VERSION 5.8 ;
BUSBITCHARS "[]" ;
DIVIDERCHAR "/" ;
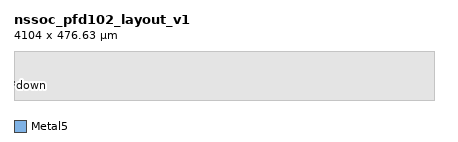
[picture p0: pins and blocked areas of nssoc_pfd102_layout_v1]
MACRO nssoc_pfd102_layout_v1
  CLASS BLOCK ;
  ORIGIN 0 0 ;
  SIZE 4104.000 BY 476.630 ;
  PIN ref
    DIRECTION INPUT ;
    USE SIGNAL ;
    PORT
      LAYER Metal5 ;
      RECT 0.000 151.430 2.000 152.630 ;
    END
  END ref
  PIN fb
    DIRECTION INPUT ;
    USE SIGNAL ;
    PORT
      LAYER Metal5 ;
      RECT 0.000 145.430 2.000 146.630 ;
    END
  END fb
  PIN reset
    DIRECTION INPUT ;
    USE SIGNAL ;
    PORT
      LAYER Metal5 ;
      RECT 0.000 157.430 2.000 158.630 ;
    END
  END reset
  PIN up
    DIRECTION OUTPUT ;
    USE SIGNAL ;
    PORT
      LAYER Metal5 ;
      RECT 0.000 169.430 2.000 170.630 ;
    END
  END up
  PIN down
    DIRECTION OUTPUT ;
    USE SIGNAL ;
    PORT
      LAYER Metal5 ;
      RECT 0.000 139.430 2.000 140.630 ;
    END
  END down
  PIN vdd
    DIRECTION INOUT ;
    USE POWER ;
    PORT
      LAYER Metal5 ;
      RECT 0.000 175.430 2.000 176.630 ;
    END
  END vdd
  PIN vss
    DIRECTION INOUT ;
    USE GROUND ;
    PORT
      LAYER Metal5 ;
      RECT 0.000 181.430 2.000 182.630 ;
    END
  END vss
  PIN sub
    DIRECTION INOUT ;
    USE GROUND ;
    PORT
      LAYER Metal5 ;
      RECT 0.000 163.430 2.000 164.630 ;
    END
  END sub
  OBS
    LAYER Metal1 ;
      RECT 0.000 0.000 4104.000 476.630 ;
    LAYER Metal2 ;
      RECT 0.000 0.000 4104.000 476.630 ;
    LAYER Metal3 ;
      RECT 0.000 0.000 4104.000 476.630 ;
    LAYER Metal4 ;
      RECT 0.000 0.000 4104.000 476.630 ;
    LAYER Metal5 ;
      RECT 0.000 0.000 4104.000 139.430 ;
      RECT 2.000 139.430 4104.000 140.630 ;
      RECT 0.000 140.630 4104.000 145.430 ;
      RECT 2.000 145.430 4104.000 146.630 ;
      RECT 0.000 146.630 4104.000 151.430 ;
      RECT 2.000 151.430 4104.000 152.630 ;
      RECT 0.000 152.630 4104.000 157.430 ;
      RECT 2.000 157.430 4104.000 158.630 ;
      RECT 0.000 158.630 4104.000 163.430 ;
      RECT 2.000 163.430 4104.000 164.630 ;
      RECT 0.000 164.630 4104.000 169.430 ;
      RECT 2.000 169.430 4104.000 170.630 ;
      RECT 0.000 170.630 4104.000 175.430 ;
      RECT 2.000 175.430 4104.000 176.630 ;
      RECT 0.000 176.630 4104.000 181.430 ;
      RECT 2.000 181.430 4104.000 182.630 ;
      RECT 0.000 182.630 4104.000 476.630 ;
    LAYER TopMetal1 ;
      RECT 0.000 0.000 4104.000 476.630 ;
    LAYER TopMetal2 ;
      RECT 0.000 0.000 4104.000 476.630 ;
  END
END nssoc_pfd102_layout_v1
END LIBRARY
